One B-rep face of a CAD part: STEP entity #114377.
In plain terms, the planar face has unit normal (0, -0.174, 0.985).
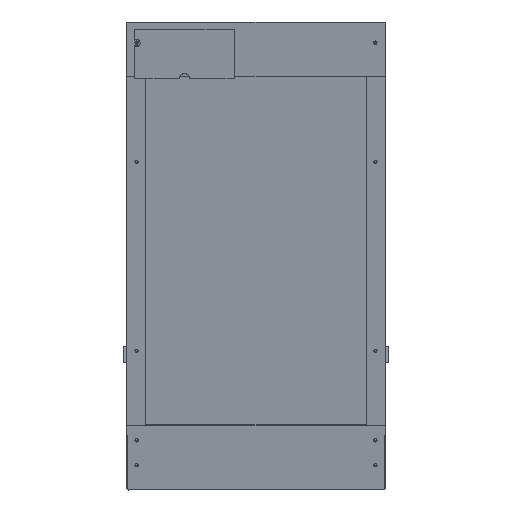
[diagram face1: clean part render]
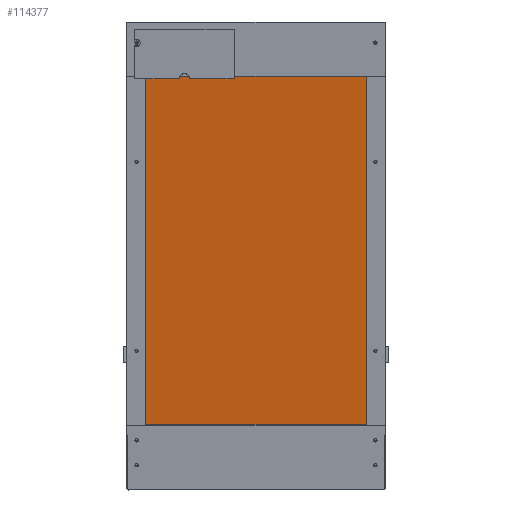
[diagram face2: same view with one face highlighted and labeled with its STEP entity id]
Its self-contained STEP definition (entity closure, numbers rounded to 3 decimals):
#114208 = PLANE('',#114209);
#114209 = AXIS2_PLACEMENT_3D('',#114210,#114211,#114212);
#114210 = CARTESIAN_POINT('',(18.1,64.,86.285));
#114211 = DIRECTION('',(-0.,1.,0.));
#114212 = DIRECTION('',(0.,0.,-1.));
#114236 = PLANE('',#114237);
#114237 = AXIS2_PLACEMENT_3D('',#114238,#114239,#114240);
#114238 = CARTESIAN_POINT('',(241.9,240.675,111.437));
#114239 = DIRECTION('',(1.,0.,0.));
#114240 = DIRECTION('',(-0.,0.,1.));
#114264 = PLANE('',#114265);
#114265 = AXIS2_PLACEMENT_3D('',#114266,#114267,#114268);
#114266 = CARTESIAN_POINT('',(18.1,417.349,136.59));
#114267 = DIRECTION('',(0.,-1.,0.));
#114268 = DIRECTION('',(0.,0.,1.));
#114290 = PLANE('',#114291);
#114291 = AXIS2_PLACEMENT_3D('',#114292,#114293,#114294);
#114292 = CARTESIAN_POINT('',(18.1,240.675,111.437));
#114293 = DIRECTION('',(1.,0.,0.));
#114294 = DIRECTION('',(-0.,0.,1.));
#114307 = VERTEX_POINT('',#114308);
#114308 = CARTESIAN_POINT('',(241.9,417.349,148.59));
#114329 = EDGE_CURVE('',#114330,#114307,#114332,.T.);
#114330 = VERTEX_POINT('',#114331);
#114331 = CARTESIAN_POINT('',(18.1,417.349,148.59));
#114332 = SURFACE_CURVE('',#114333,(#114337,#114344),.PCURVE_S1.);
#114333 = LINE('',#114334,#114335);
#114334 = CARTESIAN_POINT('',(18.1,417.349,148.59));
#114335 = VECTOR('',#114336,1.);
#114336 = DIRECTION('',(1.,0.,0.));
#114337 = PCURVE('',#114264,#114338);
#114338 = DEFINITIONAL_REPRESENTATION('',(#114339),#114343);
#114339 = LINE('',#114340,#114341);
#114340 = CARTESIAN_POINT('',(12.,0.));
#114341 = VECTOR('',#114342,1.);
#114342 = DIRECTION('',(0.,-1.));
#114343 = ( GEOMETRIC_REPRESENTATION_CONTEXT(2) 
PARAMETRIC_REPRESENTATION_CONTEXT() REPRESENTATION_CONTEXT('2D SPACE',''
  ) );
#114344 = PCURVE('',#114345,#114350);
#114345 = PLANE('',#114346);
#114346 = AXIS2_PLACEMENT_3D('',#114347,#114348,#114349);
#114347 = CARTESIAN_POINT('',(18.1,417.349,148.59));
#114348 = DIRECTION('',(0.,0.174,-0.985));
#114349 = DIRECTION('',(0.,-0.985,-0.174));
#114350 = DEFINITIONAL_REPRESENTATION('',(#114351),#114355);
#114351 = LINE('',#114352,#114353);
#114352 = CARTESIAN_POINT('',(0.,0.));
#114353 = VECTOR('',#114354,1.);
#114354 = DIRECTION('',(0.,-1.));
#114355 = ( GEOMETRIC_REPRESENTATION_CONTEXT(2) 
PARAMETRIC_REPRESENTATION_CONTEXT() REPRESENTATION_CONTEXT('2D SPACE',''
  ) );
#114377 = ADVANCED_FACE('',(#114378),#114345,.F.);
#114378 = FACE_BOUND('',#114379,.F.);
#114379 = EDGE_LOOP('',(#114380,#114381,#114404,#114427));
#114380 = ORIENTED_EDGE('',*,*,#114329,.T.);
#114381 = ORIENTED_EDGE('',*,*,#114382,.T.);
#114382 = EDGE_CURVE('',#114307,#114383,#114385,.T.);
#114383 = VERTEX_POINT('',#114384);
#114384 = CARTESIAN_POINT('',(241.9,64.,86.285));
#114385 = SURFACE_CURVE('',#114386,(#114390,#114397),.PCURVE_S1.);
#114386 = LINE('',#114387,#114388);
#114387 = CARTESIAN_POINT('',(241.9,417.349,148.59));
#114388 = VECTOR('',#114389,1.);
#114389 = DIRECTION('',(0.,-0.985,-0.174));
#114390 = PCURVE('',#114345,#114391);
#114391 = DEFINITIONAL_REPRESENTATION('',(#114392),#114396);
#114392 = LINE('',#114393,#114394);
#114393 = CARTESIAN_POINT('',(0.,-223.8));
#114394 = VECTOR('',#114395,1.);
#114395 = DIRECTION('',(1.,0.));
#114396 = ( GEOMETRIC_REPRESENTATION_CONTEXT(2) 
PARAMETRIC_REPRESENTATION_CONTEXT() REPRESENTATION_CONTEXT('2D SPACE',''
  ) );
#114397 = PCURVE('',#114236,#114398);
#114398 = DEFINITIONAL_REPRESENTATION('',(#114399),#114403);
#114399 = LINE('',#114400,#114401);
#114400 = CARTESIAN_POINT('',(37.152,-176.675));
#114401 = VECTOR('',#114402,1.);
#114402 = DIRECTION('',(-0.174,0.985));
#114403 = ( GEOMETRIC_REPRESENTATION_CONTEXT(2) 
PARAMETRIC_REPRESENTATION_CONTEXT() REPRESENTATION_CONTEXT('2D SPACE',''
  ) );
#114404 = ORIENTED_EDGE('',*,*,#114405,.F.);
#114405 = EDGE_CURVE('',#114406,#114383,#114408,.T.);
#114406 = VERTEX_POINT('',#114407);
#114407 = CARTESIAN_POINT('',(18.1,64.,86.285));
#114408 = SURFACE_CURVE('',#114409,(#114413,#114420),.PCURVE_S1.);
#114409 = LINE('',#114410,#114411);
#114410 = CARTESIAN_POINT('',(18.1,64.,86.285));
#114411 = VECTOR('',#114412,1.);
#114412 = DIRECTION('',(1.,0.,0.));
#114413 = PCURVE('',#114345,#114414);
#114414 = DEFINITIONAL_REPRESENTATION('',(#114415),#114419);
#114415 = LINE('',#114416,#114417);
#114416 = CARTESIAN_POINT('',(358.8,0.));
#114417 = VECTOR('',#114418,1.);
#114418 = DIRECTION('',(0.,-1.));
#114419 = ( GEOMETRIC_REPRESENTATION_CONTEXT(2) 
PARAMETRIC_REPRESENTATION_CONTEXT() REPRESENTATION_CONTEXT('2D SPACE',''
  ) );
#114420 = PCURVE('',#114208,#114421);
#114421 = DEFINITIONAL_REPRESENTATION('',(#114422),#114426);
#114422 = LINE('',#114423,#114424);
#114423 = CARTESIAN_POINT('',(0.,0.));
#114424 = VECTOR('',#114425,1.);
#114425 = DIRECTION('',(0.,-1.));
#114426 = ( GEOMETRIC_REPRESENTATION_CONTEXT(2) 
PARAMETRIC_REPRESENTATION_CONTEXT() REPRESENTATION_CONTEXT('2D SPACE',''
  ) );
#114427 = ORIENTED_EDGE('',*,*,#114428,.F.);
#114428 = EDGE_CURVE('',#114330,#114406,#114429,.T.);
#114429 = SURFACE_CURVE('',#114430,(#114434,#114441),.PCURVE_S1.);
#114430 = LINE('',#114431,#114432);
#114431 = CARTESIAN_POINT('',(18.1,417.349,148.59));
#114432 = VECTOR('',#114433,1.);
#114433 = DIRECTION('',(0.,-0.985,-0.174));
#114434 = PCURVE('',#114345,#114435);
#114435 = DEFINITIONAL_REPRESENTATION('',(#114436),#114440);
#114436 = LINE('',#114437,#114438);
#114437 = CARTESIAN_POINT('',(0.,0.));
#114438 = VECTOR('',#114439,1.);
#114439 = DIRECTION('',(1.,0.));
#114440 = ( GEOMETRIC_REPRESENTATION_CONTEXT(2) 
PARAMETRIC_REPRESENTATION_CONTEXT() REPRESENTATION_CONTEXT('2D SPACE',''
  ) );
#114441 = PCURVE('',#114290,#114442);
#114442 = DEFINITIONAL_REPRESENTATION('',(#114443),#114447);
#114443 = LINE('',#114444,#114445);
#114444 = CARTESIAN_POINT('',(37.152,-176.675));
#114445 = VECTOR('',#114446,1.);
#114446 = DIRECTION('',(-0.174,0.985));
#114447 = ( GEOMETRIC_REPRESENTATION_CONTEXT(2) 
PARAMETRIC_REPRESENTATION_CONTEXT() REPRESENTATION_CONTEXT('2D SPACE',''
  ) );
